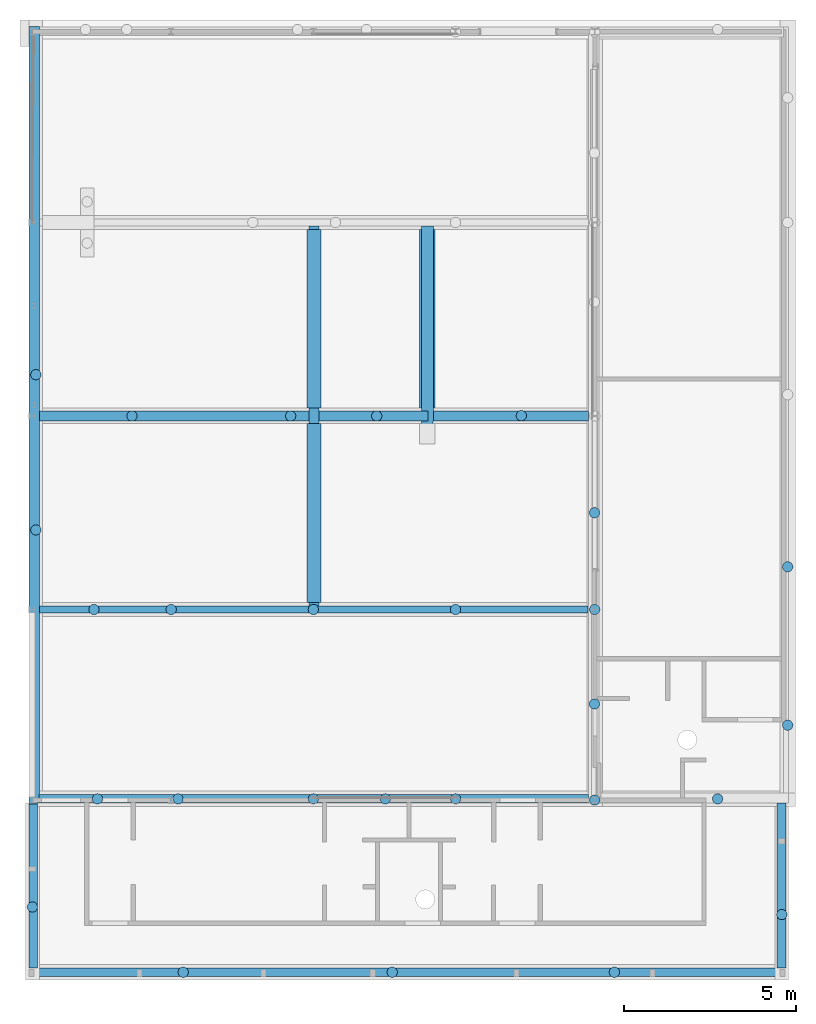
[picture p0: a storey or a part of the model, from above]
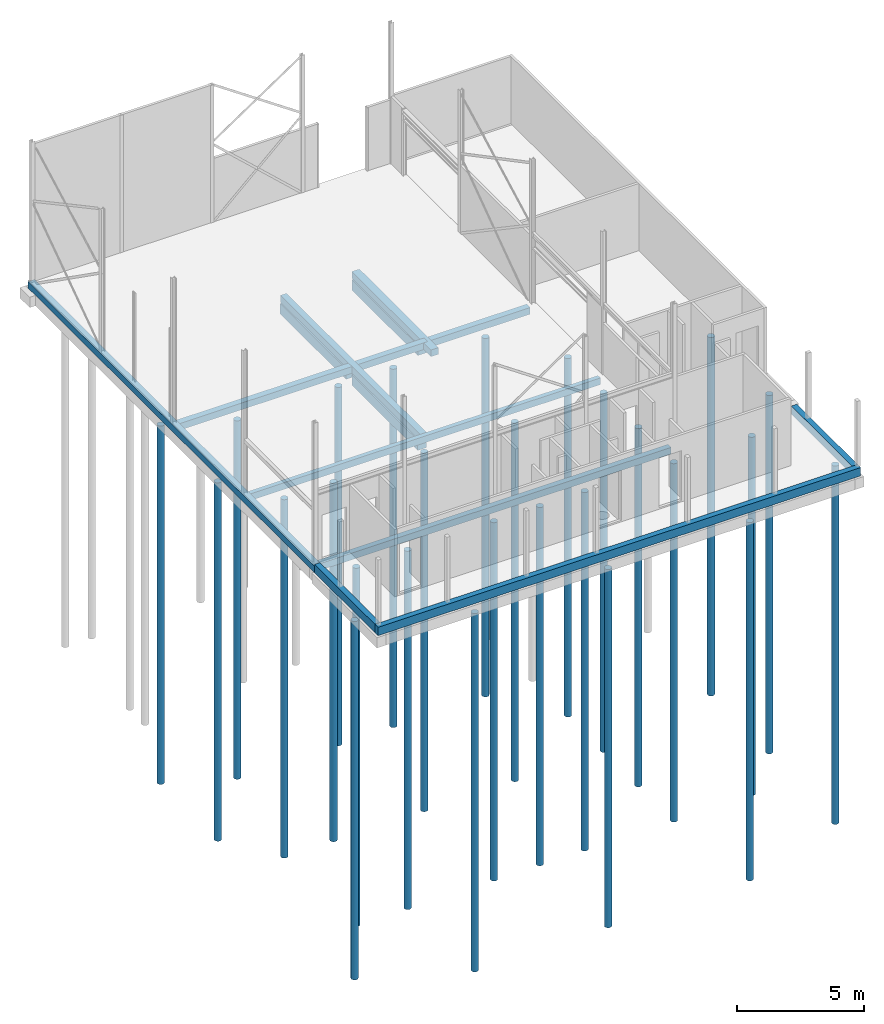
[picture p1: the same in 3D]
Properties of the parts of a building model (IFC2X3)

# File
Description: ViewDefinition [CoordinationView_V2.0], RevitIdentifiers [VersionGUID: 5828a532-ac90-4edb-b70e-f4cb268a2d0f, NumberOfSaves: 146], ExchangeRequirement [], CoordinateReference [CoordinateBase: Shared Coordinates]
File name: 24 144_Zevenbergen - Gymzaal_rvt22.ifc
Time: 2025-10-30T11:12:50
Organization: Dantuma-Wegkamp B.V.
Written by: ODA IFC SDK 22.8
Made in: 22.1.80.32 - IFC 22.7.0.0 - Default UI

# IfcProject, 24 144
LongName: Zevenbergen; Phase: Bouwaanvraag

# IfcSite, Default
RefLatitude: 52, 41, 47, 423400; RefLongitude: 6, 11, 40, 608444; RefElevation: 0 mm

# IfcBuildingStorey: Level:07_DW_Hoogte + naam (3)
Name | LongName | Elevation (mm)
00 begane grond | Peil | 0
01 eerste verdieping | 1e Verdieping | 3410
02 tweede verdieping | 2e Verdieping | 6700

# IfcBeam: 28_SF_LIB_HEA ligger_dw:HE140A (S235) (4)
Type - BIM Basis ILS - 4.3 Dragend: yes; 4.4 Uitwendig: no; 3.4 Entiteit: IfcBeam; 3.6 Codering - NL-SfB: 28.11; 3.6 NL-SfB omschrijving: hoofddraagconstructies - kolommen en liggers, kolom-/liggerconstructies; 4.7 Materiaal: constructiestaal S235
Classification: 28.11 Uniformat (Uniformat); Material: constructiestaal S235
BIM Basis ILS - 3.5 Naamgeving element: HE140A (S235); 3.5 Type: HE140A (S235)
Name (28_SF_LIB_HEA ligger_dw:HE140A (S235):...) | In
14341356 | 02 tweede verdieping
14342842 | 02 tweede verdieping | Group: Model Group:Group 1:14372738
14372881 | 02 tweede verdieping
14642640 | 01 eerste verdieping

# IfcBeam: 28_SF_LIB_HEA ligger_dw:HE160A (S235) (12)
Type - BIM Basis ILS - 4.3 Dragend: yes; 4.4 Uitwendig: no; 3.4 Entiteit: IfcBeam; 3.6 Codering - NL-SfB: 28.11; 3.6 NL-SfB omschrijving: hoofddraagconstructies - kolommen en liggers, kolom-/liggerconstructies; 4.7 Materiaal: constructiestaal S235
Classification: 28.11 Uniformat (Uniformat); Material: constructiestaal S235
BIM Basis ILS - 3.5 Naamgeving element: HE160A (S235); 3.5 Type: HE160A (S235)
Name (28_SF_LIB_HEA ligger_dw:HE160A (S235):...) | In
14295871 | 02 tweede verdieping | BIM Basis ILS - 4.5 Brandwerendheid: N.t.b.; 4.8 Brandwerendheid hoofddraagconstructie: N.t.b.
14296081 | 02 tweede verdieping
14296679 | 02 tweede verdieping
14296812 | 02 tweede verdieping
14296827 | 02 tweede verdieping
14297021 | 02 tweede verdieping
14297023 | 02 tweede verdieping
14297025 | 02 tweede verdieping
14297027 | 02 tweede verdieping
14328723 | 02 tweede verdieping
14577851 | 02 tweede verdieping | BIM Basis ILS - 4.5 Brandwerendheid: N.t.b.; 4.8 Brandwerendheid hoofddraagconstructie: N.t.b.
14590189 | 01 eerste verdieping

# IfcBeam: 28_SF_LIB_HEA ligger_dw:HE200A (S235) (5)
Type - BIM Basis ILS - 4.3 Dragend: yes; 4.4 Uitwendig: no; 3.4 Entiteit: IfcBeam; 3.6 Codering - NL-SfB: 28.11; 3.6 NL-SfB omschrijving: hoofddraagconstructies - kolommen en liggers, kolom-/liggerconstructies; 4.7 Materiaal: constructiestaal S235
Classification: 28.11 Uniformat (Uniformat); Material: constructiestaal S235
BIM Basis ILS - 3.5 Naamgeving element: HE200A (S235); 3.5 Type: HE200A (S235)
Name (28_SF_LIB_HEA ligger_dw:HE200A (S235):...) | In
14325914 | 00 begane grond
14549289 | 02 tweede verdieping
14549515 | 02 tweede verdieping
14551088 | 02 tweede verdieping
14561434 | 02 tweede verdieping

# IfcBeam: 28_SF_LIB_IPE ligger_dw:IPE200 (S235) (3)
In: 02 tweede verdieping
Type - BIM Basis ILS - 4.3 Dragend: yes; 4.4 Uitwendig: no; 3.4 Entiteit: IfcBeam; 3.6 Codering - NL-SfB: 28.11; 3.6 NL-SfB omschrijving: hoofddraagconstructies - kolommen en liggers, kolom-/liggerconstructies; 4.7 Materiaal: constructiestaal S235
Classification: 28.11 Uniformat (Uniformat); Material: constructiestaal S235
BIM Basis ILS - 3.5 Naamgeving element: IPE200 (S235); 3.5 Type: IPE200 (S235)
Name (28_SF_LIB_IPE ligger_dw:IPE200 (S235):...)
14329001
14329129
14391086

# IfcBeam: 28_SF_LIB_IPE ligger_dw:IPE240 (S235) (7)
Type - BIM Basis ILS - 4.3 Dragend: yes; 3.4 Entiteit: IfcBeam; 3.6 Codering - NL-SfB: 28.11; 3.6 NL-SfB omschrijving: hoofddraagconstructies - kolommen en liggers, kolom-/liggerconstructies; 4.7 Materiaal: constructiestaal S235; 4.4 Uitwendig: no
Classification: 28.11 Uniformat (Uniformat); Material: constructiestaal S235
BIM Basis ILS - 3.5 Naamgeving element: IPE240 (S235); 3.5 Type: IPE240 (S235)
Name (28_SF_LIB_IPE ligger_dw:IPE240 (S235):...) | In
14290186 | 01 eerste verdieping
14292657 | 00 begane grond
14512281 | 00 begane grond
14513124 | 00 begane grond
14552831 | 00 begane grond
14552852 | 00 begane grond
14552968 | 00 begane grond

# IfcBeam: 28_SF_LIB_L ligger gelijkbenig_dw:L50x50x5 (S235) (18)
In: 02 tweede verdieping
Type - BIM Basis ILS - 4.3 Dragend: yes; 4.4 Uitwendig: no; 3.4 Entiteit: IfcBeam; 3.6 Codering - NL-SfB: 28.11; 3.6 NL-SfB omschrijving: hoofddraagconstructies - kolommen en liggers, kolom-/liggerconstructies; 4.7 Materiaal: constructiestaal S235
Classification: 28.11 Uniformat (Uniformat); Material: constructiestaal S235
BIM Basis ILS - 3.5 Naamgeving element: L50x50x5 (S235); 3.5 Type: L50x50x5 (S235)
Name (28_SF_LIB_L ligger gelijkbenig_dw:L50x50x5 (S235):...)
14347161
14347278
14347650
14347838
14347931
14347933
14348421
14348501
14349087
14349460
14349540
14349542
14349848
14350011
14470697
14470783
14581076
14581078

# IfcBeam: 28_SF_LIB_L ligger gelijkbenig_dw:L80x80x6 (S235) (6)
In: 02 tweede verdieping
Type - BIM Basis ILS - 4.3 Dragend: yes; 4.4 Uitwendig: no; 3.4 Entiteit: IfcBeam; 3.6 Codering - NL-SfB: 28.11; 3.6 NL-SfB omschrijving: hoofddraagconstructies - kolommen en liggers, kolom-/liggerconstructies; 4.7 Materiaal: constructiestaal S235
Classification: 28.11 Uniformat (Uniformat); Material: constructiestaal S235
BIM Basis ILS - 3.5 Naamgeving element: L80x80x6 (S235); 3.5 Type: L80x80x6 (S235)
Name (28_SF_LIB_L ligger gelijkbenig_dw:L80x80x6 (S235):...)
14296928
14296930
14296932
14296934
14296959
14296990

# IfcBeam: 28_SF_LIB_UNP ligger_dw:UNP140 (S235) (23)
Type - BIM Basis ILS - 4.3 Dragend: yes; 4.4 Uitwendig: no; 3.4 Entiteit: IfcBeam; 3.6 Codering - NL-SfB: 28.11; 3.6 NL-SfB omschrijving: hoofddraagconstructies - kolommen en liggers, kolom-/liggerconstructies; 4.7 Materiaal: constructiestaal S235
Classification: 28.11 Uniformat (Uniformat); Material: constructiestaal S235
BIM Basis ILS - 3.5 Naamgeving element: UNP140 (S235); 3.5 Type: UNP140 (S235)
Name (28_SF_LIB_UNP ligger_dw:UNP140 (S235):...) | In
14398224 | 01 eerste verdieping
14399182 | 01 eerste verdieping
14399587 | 01 eerste verdieping
14402766 | 00 begane grond
14408845 | 02 tweede verdieping
14409364 | 02 tweede verdieping
14409934 | 01 eerste verdieping
14410029 | 01 eerste verdieping
14410105 | 01 eerste verdieping
14410157 | 01 eerste verdieping
14410337 | 01 eerste verdieping
14410354 | 01 eerste verdieping
14410582 | 01 eerste verdieping
14410927 | 01 eerste verdieping
14410929 | 01 eerste verdieping
14411169 | 01 eerste verdieping
14411171 | 01 eerste verdieping
14411344 | 01 eerste verdieping
14411425 | 01 eerste verdieping
14411487 | 01 eerste verdieping
14411551 | 01 eerste verdieping
14412489 | 01 eerste verdieping
14412908 | 01 eerste verdieping

# IfcBeam: 28_SF_LIB_UNP ligger_dw:UNP160 (S235) (4)
Type - BIM Basis ILS - 4.3 Dragend: yes; 4.4 Uitwendig: no; 3.4 Entiteit: IfcBeam; 3.6 Codering - NL-SfB: 28.11; 3.6 NL-SfB omschrijving: hoofddraagconstructies - kolommen en liggers, kolom-/liggerconstructies; 4.7 Materiaal: constructiestaal S235
Classification: 28.11 Uniformat (Uniformat); Material: constructiestaal S235
BIM Basis ILS - 3.5 Naamgeving element: UNP160 (S235); 3.5 Type: UNP160 (S235)
Name (28_SF_LIB_UNP ligger_dw:UNP160 (S235):...) | In
14339130 | 01 eerste verdieping
14387959 | 01 eerste verdieping
14400505 | 01 eerste verdieping
14402275 | 00 begane grond

# IfcBeam: 28_SF_LIB_UNP ligger_dw:UNP180 (S235), 28_SF_LIB_UNP ligger_dw:UNP180 (S235):14643737
In: 01 eerste verdieping
Type - BIM Basis ILS - 4.3 Dragend: yes; 4.4 Uitwendig: no; 3.4 Entiteit: IfcBeam; 3.6 Codering - NL-SfB: 28.11; 3.6 NL-SfB omschrijving: hoofddraagconstructies - kolommen en liggers, kolom-/liggerconstructies; 4.7 Materiaal: constructiestaal S235
Classification: 28.11 Uniformat (Uniformat); Material: constructiestaal S235
BIM Basis ILS - 3.5 Naamgeving element: UNP180 (S235); 3.5 Type: UNP180 (S235)

# IfcBeam: 28_SF_LIB_UNP ligger_dw:UNP240 (S235) (7)
Type - BIM Basis ILS - 4.3 Dragend: yes; 4.4 Uitwendig: no; 3.4 Entiteit: IfcBeam; 3.6 Codering - NL-SfB: 28.11; 3.6 NL-SfB omschrijving: hoofddraagconstructies - kolommen en liggers, kolom-/liggerconstructies; 4.7 Materiaal: constructiestaal S235
Classification: 28.11 Uniformat (Uniformat); Material: constructiestaal S235; Group: Model Group:kader:14382562
BIM Basis ILS - 3.5 Naamgeving element: UNP240 (S235); 3.5 Type: UNP240 (S235)
Name (28_SF_LIB_UNP ligger_dw:UNP240 (S235):...) | In
14382544 | 01 eerste verdieping
14382546 | 01 eerste verdieping
14382549 | 01 eerste verdieping
14382552 | 01 eerste verdieping
14382555 | 01 eerste verdieping
14382557 | 02 tweede verdieping
14382559 | 01 eerste verdieping

# IfcBeam: 28_SF_LIB_houten ligger rechthoekig_dw:200x1050 (GL28h), 28_SF_LIB_houten ligger rechthoekig_dw:200x1050 (GL28h):14293752
In: 01 eerste verdieping
Type - BIM Basis ILS - 4.3 Dragend: yes; 4.4 Uitwendig: yes; 3.4 Entiteit: IfcBeam; 3.6 Codering - NL-SfB: 28.11; 3.6 NL-SfB omschrijving: hoofddraagconstructies - kolommen en liggers, kolom-/liggerconstructies; 4.7 Materiaal: constructiehout GL28h
Classification: 28.11 Uniformat (Uniformat); Material: constructiehout GL28h
BIM Basis ILS - 3.5 Naamgeving element: 200x1050 (GL28h); 3.5 Type: 200x1050 (GL28h); 4.5 Brandwerendheid: N.t.b.; 4.8 Brandwerendheid hoofddraagconstructie: N.t.b.

# IfcBeam: 28_SF_LIB_houten ligger rechthoekig_dw:200x960 (GL28h) (2)
In: 02 tweede verdieping
Type - BIM Basis ILS - 4.3 Dragend: yes; 4.4 Uitwendig: yes; 3.4 Entiteit: IfcBeam; 3.6 Codering - NL-SfB: 28.11; 3.6 NL-SfB omschrijving: hoofddraagconstructies - kolommen en liggers, kolom-/liggerconstructies; 4.7 Materiaal: constructiehout GL28h
Classification: 28.11 Uniformat (Uniformat); Material: constructiehout GL28h
BIM Basis ILS - 3.5 Naamgeving element: 200x960 (GL28h); 3.5 Type: 200x960 (GL28h); 4.5 Brandwerendheid: N.t.b.; 4.8 Brandwerendheid hoofddraagconstructie: N.t.b.
Name (28_SF_LIB_houten ligger rechthoekig_dw:200x960 (GL28h):...) | Group
14291663 | Model Group:SPANT:14293701
14293783 | Model Group:SPANT:14293785

# IfcBeam: 28_SF_LIB_houten ligger rechthoekig_dw:70x245 (C24) (87)
In: 01 eerste verdieping
Type - BIM Basis ILS - 4.3 Dragend: yes; 4.4 Uitwendig: yes; 3.4 Entiteit: IfcBeam; 3.6 Codering - NL-SfB: 28.11; 3.6 NL-SfB omschrijving: hoofddraagconstructies - kolommen en liggers, kolom-/liggerconstructies; 4.7 Materiaal: constructiehout C24
Classification: 28.11 Uniformat (Uniformat); Material: constructiehout C24
BIM Basis ILS - 3.5 Naamgeving element: 70x245 (C24); 3.5 Type: 70x245 (C24)
Name (28_SF_LIB_houten ligger rechthoekig_dw:70x245 (C24):...)
14288473
14288544
14288929
14289023
14300772
14313485
14313488
14313491
14313494
14313497
14313500
14313503
14313506
14313509
14313512
14313515
14313518
14313521
14313524
14313527
14313530
14313533
14313536
14313539
14313542
14313545
14313548
14313551
14313554
14313557
14313560
14313563
14313566
14313569
14313572
14313575
14313578
14313581
14313584
14313587
14313590
14313593
14313596
14313599
14313602
14313605
14313608
14313611
14313614
14313617
14313620
14313623
14313626
14313629
14313632
14313635
14313638
14313641
14314583
14314586
14314589
14314592
14314595
14314598
14314601
14314604
14314607
14314610
14314613
14314616
14314619
14314622
14314625
14314784
14314787
14314790
14314793
14314796
14314799
14314802
14314805
14314808
14314811
14314814
14314817
14382725
14382727

# IfcBeam: 28_SF_LIB_koker ligger_dw:K60x60x6 (S275) (6)
In: 02 tweede verdieping
Type - BIM Basis ILS - 4.3 Dragend: yes; 4.4 Uitwendig: no; 3.4 Entiteit: IfcBeam; 3.6 Codering - NL-SfB: 28.11; 3.6 NL-SfB omschrijving: hoofddraagconstructies - kolommen en liggers, kolom-/liggerconstructies; 4.7 Materiaal: constructiestaal S275
Classification: 28.11 Uniformat (Uniformat); Material: constructiestaal S275
BIM Basis ILS - 3.5 Naamgeving element: K60x60x6 (S275); 3.5 Type: K60x60x6 (S275)
Name (28_SF_LIB_koker ligger_dw:K60x60x6 (S275):...)
14296961
14296963
14296965
14296992
14296994
14296996

# IfcBeam: 28_SF_LIB_strip ligger_dw:strip 100x8 (S235) (16)
In: 00 begane grond
Type - BIM Basis ILS - 4.3 Dragend: yes; 4.4 Uitwendig: no; 3.4 Entiteit: IfcBeam; 3.6 Codering - NL-SfB: 28.11; 3.6 NL-SfB omschrijving: hoofddraagconstructies - kolommen en liggers, kolom-/liggerconstructies; 4.7 Materiaal: constructiestaal S235
Classification: 28.11 Uniformat (Uniformat); Material: constructiestaal S235
BIM Basis ILS - 3.5 Naamgeving element: strip 100x8 (S235); 3.5 Type: strip 100x8 (S235)
Name (28_SF_LIB_strip ligger_dw:strip 100x8 (S235):...)
14340948
14341179
14341295
14341358
14341360
14341362
14341364
14343473 | Group: Model Group:Group 1:14372738
14343555 | Group: Model Group:Group 1:14372738
14343773 | Group: Model Group:Group 1:14372738
14344218 | Group: Model Group:Group 1:14372738
14372883
14372885
14372889
14459453
14463984

# IfcBeam: 28_SF_UN_koker ligger_dw:K180x180x10 (S355) (5)
Type - BIM Basis ILS - 4.3 Dragend: yes; 4.4 Uitwendig: no; 3.4 Entiteit: IfcBeam; 3.6 Codering - NL-SfB: 28.11; 3.6 NL-SfB omschrijving: hoofddraagconstructies - kolommen en liggers, kolom-/liggerconstructies; 4.7 Materiaal: constructiestaal S355
Classification: 28.11 Uniformat (Uniformat); Material: constructiestaal S355
BIM Basis ILS - 3.5 Naamgeving element: K180x180x10 (S355); 3.5 Type: K180x180x10 (S355)
Name (28_SF_UN_koker ligger_dw:K180x180x10 (S355):...) | In
14571354 | 00 begane grond
14571927 | 01 eerste verdieping
14572121 | 01 eerste verdieping
14572268 | 01 eerste verdieping
14572367 | 01 eerste verdieping

# IfcBeam: 28_SF_UN_raveelijzer_dw:raveelijzer - vloer 200 (2)
In: 01 eerste verdieping
Type - PredefinedType: BEAM; Classification: 28.11 Uniformat (Uniformat); Material: constructiestaal
Type - BIM Basis ILS - 4.3 Dragend: yes; 4.4 Uitwendig: no; 3.4 Entiteit: IfcBeam; 3.6 Codering - NL-SfB: 28.11; 3.6 NL-SfB omschrijving: hoofddraagconstructies - kolommen en liggers, kolom-/liggerconstructies; 4.7 Materiaal: constructiestaal
BIM Basis ILS - 3.5 Naamgeving element: raveelijzer - vloer 200; 3.5 Type: raveelijzer - vloer 200
Name (28_SF_UN_raveelijzer_dw:raveelijzer - vloer 200:...)
14405406
14405581

# IfcBuildingElementProxy: 00_GM_UN_referentiekubus_dw:referentiekubus l-v-o, 00_GM_UN_referentiekubus_dw:referentiekubus l-v-o:8439740
In: 00 begane grond
Type - Classification: 0-.00 Uniformat (Uniformat); Material: DW groen - 176-172-60, DW bruin - 64-48-0
Type - BIM Basis ILS - 3.4 Entiteit: IfcObject; 3.6 Codering - NL-SfB: 0-.00; 3.6 NL-SfB omschrijving: indirecte projectvoorzieningen
BIM Basis ILS - 3.5 Naamgeving element: referentiekubus l-v-o; 3.5 Type: referentiekubus l-v-o

# IfcColumn: 28_SCO_TLB_HEA kolom_dw:HE160A (S235) (7)
In: 00 begane grond
Type - PredefinedType: COLUMN; Classification: 28.11 Uniformat (Uniformat); Material: constructiestaal S235
Type - BIM Basis ILS - 4.3 Dragend: yes; 4.4 Uitwendig: yes; 3.4 Entiteit: IfcColumn; 3.6 Codering - NL-SfB: 28.11; 3.6 NL-SfB omschrijving: hoofddraagconstructies - kolommen en liggers, kolom-/liggerconstructies; 4.7 Materiaal: constructiestaal S235
BIM Basis ILS - 3.5 Naamgeving element: HE160A (S235); 3.5 Type: HE160A (S235)
Name (28_SCO_TLB_HEA kolom_dw:HE160A (S235):...)
14284300 | Group: Model Group:SK2:14284304
14284488 | Group: Model Group:SK2:14284492
14284511 | Group: Model Group:SK2:14284515
14284992
14285208
14285229
14353443

# IfcColumn: 28_SCO_TLB_HEA kolom_dw:HE180A (S235) (10)
In: 00 begane grond
Type - PredefinedType: COLUMN; Classification: 28.11 Uniformat (Uniformat); Material: constructiestaal S235
Type - BIM Basis ILS - 4.3 Dragend: yes; 4.4 Uitwendig: yes; 3.4 Entiteit: IfcColumn; 3.6 Codering - NL-SfB: 28.11; 3.6 NL-SfB omschrijving: hoofddraagconstructies - kolommen en liggers, kolom-/liggerconstructies; 4.7 Materiaal: constructiestaal S235
BIM Basis ILS - 3.5 Naamgeving element: HE180A (S235); 3.5 Type: HE180A (S235)
Name (28_SCO_TLB_HEA kolom_dw:HE180A (S235):...)
14284682 | Group: Model Group:SPANT:14293701
14285795 | Group: Model Group:SPANT:14293701
14293748
14293750
14293779 | Group: Model Group:SPANT:14293785
14293781 | Group: Model Group:SPANT:14293785
14295869
14295873
14578198
14578254

# IfcColumn: 28_SCO_TLB_IPE kolom_dw:IPE160 (S235) (8)
In: 01 eerste verdieping
Type - PredefinedType: COLUMN; Classification: 28.11 Uniformat (Uniformat); Material: constructiestaal S235
Type - BIM Basis ILS - 4.3 Dragend: yes; 4.4 Uitwendig: yes; 3.4 Entiteit: IfcColumn; 3.6 Codering - NL-SfB: 28.11; 3.6 NL-SfB omschrijving: hoofddraagconstructies - kolommen en liggers, kolom-/liggerconstructies; 4.7 Materiaal: constructiestaal S235
BIM Basis ILS - 3.5 Naamgeving element: IPE160 (S235); 3.5 Type: IPE160 (S235)
Name (28_SCO_TLB_IPE kolom_dw:IPE160 (S235):...)
14328455
14328642
14328661
14329676
14381776
14392654
14409115
14409175

# IfcColumn: 28_SCO_TLB_UNP kolom_dw:UNP140 (S235) (4)
In: 01 eerste verdieping
Type - PredefinedType: COLUMN; Classification: 28.11 Uniformat (Uniformat); Material: constructiestaal S235
Type - BIM Basis ILS - 4.3 Dragend: yes; 4.4 Uitwendig: yes; 3.4 Entiteit: IfcColumn; 3.6 Codering - NL-SfB: 28.11; 3.6 NL-SfB omschrijving: hoofddraagconstructies - kolommen en liggers, kolom-/liggerconstructies; 4.7 Materiaal: constructiestaal S235
BIM Basis ILS - 3.5 Naamgeving element: UNP140 (S235); 3.5 Type: UNP140 (S235)
Name (28_SCO_TLB_UNP kolom_dw:UNP140 (S235):...)
14398592
14398738
14410425
14410427

# IfcColumn: 28_SCO_TLB_UNP kolom_dw:UNP160 (S235) (5)
In: 00 begane grond
Type - PredefinedType: COLUMN; Classification: 28.11 Uniformat (Uniformat); Material: constructiestaal S235
Type - BIM Basis ILS - 4.3 Dragend: yes; 4.4 Uitwendig: yes; 3.4 Entiteit: IfcColumn; 3.6 Codering - NL-SfB: 28.11; 3.6 NL-SfB omschrijving: hoofddraagconstructies - kolommen en liggers, kolom-/liggerconstructies; 4.7 Materiaal: constructiestaal S235
BIM Basis ILS - 3.5 Naamgeving element: UNP160 (S235); 3.5 Type: UNP160 (S235)
Name (28_SCO_TLB_UNP kolom_dw:UNP160 (S235):...)
14387786
14388673
14402511
14555188
14555243

# IfcColumn: 28_SCO_TLB_houten kolom rechthoekig_dw:150x200 (C24) (9)
In: 00 begane grond
Type - PredefinedType: COLUMN; Classification: 28.11 Uniformat (Uniformat); Material: constructiehout C24
Type - BIM Basis ILS - 4.3 Dragend: yes; 4.4 Uitwendig: yes; 3.4 Entiteit: IfcColumn; 3.6 Codering - NL-SfB: 28.11; 3.6 NL-SfB omschrijving: hoofddraagconstructies - kolommen en liggers, kolom-/liggerconstructies; 4.7 Materiaal: constructiehout C24
BIM Basis ILS - 3.5 Naamgeving element: 150x200 (C24); 3.5 Type: 150x200 (C24)
Name (28_SCO_TLB_houten kolom rechthoekig_dw:150x200 (C24):...) | Group
14282308
14283523
14283591 | Model Group:HK1:14283595
14283735 | Model Group:HK1:14283739
14283756 | Model Group:HK1:14283760
14283779 | Model Group:HK1:14283783
14283800 | Model Group:HK1:14283804
14283819
14366132

# IfcFooting: 16_SF_LIB_funderingsbalk_dw:150x400 (ihwg), 16_SF_LIB_funderingsbalk_dw:150x400 (ihwg):14532306
In: 00 begane grond
Type - Classification: 16.11 Uniformat (Uniformat); Material: ihwg beton
BIM Basis ILS - 4.3 Dragend: yes; 3.4 Entiteit: IfcFooting; 3.5 Naamgeving element: 150x400 (ihwg); 3.5 Type: 150x400 (ihwg); 3.6 Codering - NL-SfB: 16.11; 3.6 NL-SfB omschrijving: funderingsconstructies - voeten en balken, fundatie voeten; 4.7 Materiaal: ihwg beton; 4.8 Brandwerendheid hoofddraagconstructie: N.t.b.

# IfcFooting: 16_SF_LIB_funderingsbalk_dw:200x350 (ihwg) (2)
In: 00 begane grond
Type - Classification: 16.11 Uniformat (Uniformat); Material: ihwg beton
BIM Basis ILS - 4.3 Dragend: yes; 3.4 Entiteit: IfcFooting; 3.5 Naamgeving element: 200x350 (ihwg); 3.5 Type: 200x350 (ihwg); 3.6 Codering - NL-SfB: 16.11; 3.6 NL-SfB omschrijving: funderingsconstructies - voeten en balken, fundatie voeten; 4.7 Materiaal: ihwg beton; 4.8 Brandwerendheid hoofddraagconstructie: N.t.b.
Name (16_SF_LIB_funderingsbalk_dw:200x350 (ihwg):...)
14528531
14528994

# IfcFooting: 16_SF_LIB_funderingsbalk_dw:250x320 (ihwg) (2)
In: 00 begane grond
Type - Classification: 16.11 Uniformat (Uniformat); Material: ihwg beton
BIM Basis ILS - 4.3 Dragend: yes; 3.4 Entiteit: IfcFooting; 3.5 Naamgeving element: 250x320 (ihwg); 3.5 Type: 250x320 (ihwg); 3.6 Codering - NL-SfB: 16.11; 3.6 NL-SfB omschrijving: funderingsconstructies - voeten en balken, fundatie voeten; 4.7 Materiaal: ihwg beton; 4.8 Brandwerendheid hoofddraagconstructie: N.t.b.
Name (16_SF_LIB_funderingsbalk_dw:250x320 (ihwg):...)
14445392
14450429

# IfcFooting: 16_SF_LIB_funderingsbalk_dw:250x400 (ihwg) (3)
In: 00 begane grond
Type - Classification: 16.11 Uniformat (Uniformat); Material: ihwg beton
BIM Basis ILS - 4.3 Dragend: yes; 3.4 Entiteit: IfcFooting; 3.5 Naamgeving element: 250x400 (ihwg); 3.5 Type: 250x400 (ihwg); 3.6 Codering - NL-SfB: 16.11; 3.6 NL-SfB omschrijving: funderingsconstructies - voeten en balken, fundatie voeten; 4.7 Materiaal: ihwg beton; 4.8 Brandwerendheid hoofddraagconstructie: N.t.b.
Name (16_SF_LIB_funderingsbalk_dw:250x400 (ihwg):...)
14439468
14443439
14443543

# IfcFooting: 16_SF_LIB_funderingsbalk_dw:260x500 (ihwg), 16_SF_LIB_funderingsbalk_dw:260x500 (ihwg):14303276
In: 00 begane grond
Type - Classification: 16.12 Uniformat (Uniformat); Material: ihwg beton
BIM Basis ILS - 4.3 Dragend: yes; 3.4 Entiteit: IfcFooting; 3.5 Naamgeving element: 260x500 (ihwg); 3.5 Type: 260x500 (ihwg); 3.6 Codering - NL-SfB: 16.12; 3.6 NL-SfB omschrijving: funderingsconstructies - voeten en balken, fundatie balken; 4.7 Materiaal: ihwg beton; 4.8 Brandwerendheid hoofddraagconstructie: N.t.b.

# IfcFooting: 16_SF_LIB_funderingsbalk_dw:280x350 (ihwg) (4)
In: 00 begane grond
Type - Classification: 16.11 Uniformat (Uniformat); Material: ihwg beton
BIM Basis ILS - 4.3 Dragend: yes; 3.4 Entiteit: IfcFooting; 3.5 Naamgeving element: 280x350 (ihwg); 3.5 Type: 280x350 (ihwg); 3.6 Codering - NL-SfB: 16.11; 3.6 NL-SfB omschrijving: funderingsconstructies - voeten en balken, fundatie voeten; 4.7 Materiaal: ihwg beton; 4.8 Brandwerendheid hoofddraagconstructie: N.t.b.
Name (16_SF_LIB_funderingsbalk_dw:280x350 (ihwg):...)
14491663
14493827
14494834
14495136

# IfcFooting: 16_SF_LIB_funderingsbalk_dw:300x320 (ihwg) (2)
In: 00 begane grond
Type - Classification: 16.11 Uniformat (Uniformat); Material: ihwg beton
BIM Basis ILS - 4.3 Dragend: yes; 3.4 Entiteit: IfcFooting; 3.5 Naamgeving element: 300x320 (ihwg); 3.5 Type: 300x320 (ihwg); 3.6 Codering - NL-SfB: 16.11; 3.6 NL-SfB omschrijving: funderingsconstructies - voeten en balken, fundatie voeten; 4.7 Materiaal: ihwg beton; 4.8 Brandwerendheid hoofddraagconstructie: N.t.b.
Name (16_SF_LIB_funderingsbalk_dw:300x320 (ihwg):...)
14448791
14449513

# IfcFooting: 16_SF_LIB_funderingsbalk_dw:300x400 (ihwg) (2)
In: 00 begane grond
Type - Classification: 16.11 Uniformat (Uniformat); Material: ihwg beton
BIM Basis ILS - 4.3 Dragend: yes; 3.4 Entiteit: IfcFooting; 3.5 Naamgeving element: 300x400 (ihwg); 3.5 Type: 300x400 (ihwg); 3.6 Codering - NL-SfB: 16.11; 3.6 NL-SfB omschrijving: funderingsconstructies - voeten en balken, fundatie voeten; 4.7 Materiaal: ihwg beton; 4.8 Brandwerendheid hoofddraagconstructie: N.t.b.
Name (16_SF_LIB_funderingsbalk_dw:300x400 (ihwg):...)
14531801
14533458

# IfcFooting: 16_SF_LIB_funderingsbalk_dw:350x450 (ihwg), 16_SF_LIB_funderingsbalk_dw:350x450 (ihwg):14495497
In: 00 begane grond
Type - Classification: 16.11 Uniformat (Uniformat); Material: ihwg beton
BIM Basis ILS - 4.3 Dragend: yes; 3.4 Entiteit: IfcFooting; 3.5 Naamgeving element: 350x450 (ihwg); 3.5 Type: 350x450 (ihwg); 3.6 Codering - NL-SfB: 16.11; 3.6 NL-SfB omschrijving: funderingsconstructies - voeten en balken, fundatie voeten; 4.7 Materiaal: ihwg beton; 4.8 Brandwerendheid hoofddraagconstructie: N.t.b.

# IfcFooting: 16_SF_LIB_funderingsbalk_dw:400x500 (ihwg) (8)
In: 00 begane grond
Type - Classification: 16.12 Uniformat (Uniformat); Material: ihwg beton
BIM Basis ILS - 4.3 Dragend: yes; 3.4 Entiteit: IfcFooting; 3.5 Naamgeving element: 400x500 (ihwg); 3.5 Type: 400x500 (ihwg); 3.6 Codering - NL-SfB: 16.12; 3.6 NL-SfB omschrijving: funderingsconstructies - voeten en balken, fundatie balken; 4.7 Materiaal: ihwg beton; 4.8 Brandwerendheid hoofddraagconstructie: N.t.b.
Name (16_SF_LIB_funderingsbalk_dw:400x500 (ihwg):...)
14302218
14302364
14302961
14305030
14311621
14489020
14489022
14615878

# IfcFooting: 16_SF_LIB_funderingsbalk_dw:450x500 (ihwg) (8)
In: 00 begane grond
Type - Classification: 16.12 Uniformat (Uniformat); Material: ihwg beton
BIM Basis ILS - 4.3 Dragend: yes; 3.4 Entiteit: IfcFooting; 3.5 Naamgeving element: 450x500 (ihwg); 3.5 Type: 450x500 (ihwg); 3.6 Codering - NL-SfB: 16.12; 3.6 NL-SfB omschrijving: funderingsconstructies - voeten en balken, fundatie balken; 4.7 Materiaal: ihwg beton
Name (16_SF_LIB_funderingsbalk_dw:450x500 (ihwg):...) | 4.8 Brandwerendheid hoofddraagconstructie
14303714 | N.t.b.
14303831 | N.t.b.
14305015 | N.t.b.
14305122 | N.t.b.
14365426
14488232 | N.t.b.
14488643 | N.t.b.
14499392 | N.t.b.

# IfcFooting: 16_SF_LIB_funderingsbalk_dw:550x500 (ihwg), 16_SF_LIB_funderingsbalk_dw:550x500 (ihwg):14302722
In: 00 begane grond
Type - Classification: 16.12 Uniformat (Uniformat); Material: ihwg beton
BIM Basis ILS - 4.3 Dragend: yes; 3.4 Entiteit: IfcFooting; 3.5 Naamgeving element: 550x500 (ihwg); 3.5 Type: 550x500 (ihwg); 3.6 Codering - NL-SfB: 16.12; 3.6 NL-SfB omschrijving: funderingsconstructies - voeten en balken, fundatie balken; 4.7 Materiaal: ihwg beton; 4.8 Brandwerendheid hoofddraagconstructie: N.t.b.

# IfcFooting: 16_SF_LIB_funderingsbalk_dw:poer 400x600, 16_SF_LIB_funderingsbalk_dw:poer 400x600:14610776
In: 00 begane grond
Type - Classification: 16.12 Uniformat (Uniformat); Material: ihwg beton
BIM Basis ILS - 4.3 Dragend: yes; 3.4 Entiteit: IfcFooting; 3.5 Naamgeving element: poer 400x600; 3.5 Type: poer 400x600; 3.6 Codering - NL-SfB: 16.12; 3.6 NL-SfB omschrijving: funderingsconstructies - voeten en balken, fundatie balken; 4.7 Materiaal: ihwg beton; 4.8 Brandwerendheid hoofddraagconstructie: N.t.b.

# IfcOpeningElement: Opening (12)
Name | In | Classification
8 x Basic Wall:21.22_WA_TLB_kalkzandsteen 120-CS12_dw:14271793 | 00 begane grond | 21.22 Uniformat (Uniformat)
Floor:23.21_FL_LB_geïsoleerde kanaalplaatvloer 200-Rc=6,5_dw:14281954 | 00 begane grond | 23.21 Uniformat (Uniformat) | BIM Basis ILS - 3.5 Naamgeving element: Ø540 (kl); 3.5 Type: Ø540 (kl)
Floor:23.21_FL_LB_geïsoleerde kanaalplaatvloer 200-Rc=6,5_dw:14282030 | 00 begane grond | 23.21 Uniformat (Uniformat) | BIM Basis ILS - 3.5 Naamgeving element: Ø540 (kl); 3.5 Type: Ø540 (kl)
2 x Floor:23.21_FL_LB_kanaalplaatvloer 200_dw:14271668 | 01 eerste verdieping | 23.21 Uniformat (Uniformat)

# IfcPile: 17_SFO_TLB_mortelschroefpaal_dw:Ø300_ihwg fund_type 01 (46)
In: 00 begane grond
Classification: 17.12 Uniformat (Uniformat); Material: ihwg beton
BIM Basis ILS - 4.3 Dragend: yes; 3.4 Entiteit: IfcPile; 3.5 Naamgeving element: Ø300_ihwg fund_type 01; 3.5 Type: Ø300_ihwg fund_type 01; 3.6 Codering - NL-SfB: 17.12; 3.6 NL-SfB omschrijving: paalfunderingen - niet geheid, dragende palen - geschroefd; 4.7 Materiaal: ihwg beton
Name (17_SFO_TLB_mortelschroefpaal_dw:Ø300_ihwg fund_type 01:...) | 4.8 Paalnummer
14378213 | 20
14378246 | 16
14378260 | 1
14378296 | 5
14378509 | 12
14378521 | 13
14378535 | 14
14378647 | 21
14378659 | 23
14378679 | 24
14378726 | 29
14378729 | 30
14378732 | 31
14378735 | 25
14378764 | 28
14378807 | 32
14378875 | 35
14378899 | 36
14378911 | 37
14378925 | 39
14378951 | 41
14378963 | 34
14379524 | 27
14379551 | 8
14379637 | 19
14379766 | 44
14379809 | 45
14379823 | 46
14379835 | 43
14412164 | 15
14593934 | 3
14593946 | 4
14594007 | 6
14594023 | 7
14594874 | 2
14594898 | 9
14594959 | 17
14595027 | 33
14595039 | 40
14595088 | 11
14595256 | 18
14595272 | 26
14595284 | 42
14595373 | 38
14595656 | 22
14611114 | 10

# IfcSlab: Floor:23.20_FL_LB_druklaag 80_dw, Floor:23.20_FL_LB_druklaag 80_dw:14307007
In: 00 begane grond
Type - PredefinedType: FLOOR; Material: ihwg beton 80 mm
Type - BIM Basis ILS - 4.4 Uitwendig: no; 3.4 Entiteit: IfcSlab; 3.6 Codering - NL-SfB: 23.20; 3.6 NL-SfB omschrijving: vloeren - constructief, algemeen (verzamelniveau); 4.7 Materiaal: ihwg beton
Classification: 23.20 Uniformat (Uniformat)
BIM Basis ILS - 4.3 Dragend: yes; 3.5 Naamgeving element: 23.20_FL_LB_druklaag 80_dw; 3.5 Type: 23.20_FL_LB_druklaag 80_dw

# IfcSlab: Floor:23.20_FL_LB_underlayment 18_dw, Floor:23.20_FL_LB_underlayment 18_dw:14300275
In: 01 eerste verdieping
Type - PredefinedType: FLOOR; Material: underlayment 18 mm
Type - BIM Basis ILS - 4.4 Uitwendig: no; 3.4 Entiteit: IfcSlab; 3.6 Codering - NL-SfB: 23.20; 3.6 NL-SfB omschrijving: vloeren - constructief, algemeen (verzamelniveau); 4.7 Materiaal: underlayment
Classification: 23.20 Uniformat (Uniformat)
BIM Basis ILS - 4.3 Dragend: yes; 3.5 Naamgeving element: 23.20_FL_LB_underlayment 18_dw; 3.5 Type: 23.20_FL_LB_underlayment 18_dw

# IfcSlab: Floor:23.21.41_staalplaat 137 (2)
In: 02 tweede verdieping
Type - PredefinedType: FLOOR; Material: Metal Deck 137 mm
Type - BIM Basis ILS - 4.4 Uitwendig: no; 3.6 Codering - NL-SfB: 27.21; 3.6 NL-SfB omschrijving: daken - constructief, vlakke daken; 4.7 Materiaal: Metal Deck; 4.6 Warmtedoorgangscoefficient: 328,4672 W/(m²·K)
Classification: 27.21 Uniformat (Uniformat)
BIM Basis ILS - 4.3 Dragend: yes; 3.5 Naamgeving element: 23.21.41_staalplaat 137; 3.5 Type: 23.21.41_staalplaat 137
Name (Floor:23.21.41_staalplaat 137:...)
14300850
14301639

# IfcSlab: Floor:23.21_FL_LB_geïsoleerde kanaalplaatvloer 200-Rc=3,7_dw (7)
In: 00 begane grond
Type - PredefinedType: FLOOR; Material: prefab beton 200 mm, EPS vloerisolatie 120 mm
Type - BIM Basis ILS - 4.4 Uitwendig: yes; 3.4 Entiteit: IfcSlab; 3.6 Codering - NL-SfB: 23.21; 3.6 NL-SfB omschrijving: vloeren - constructief, vrijdragende vloeren; 4.7 Materiaal: prefab beton; 4.6 Isolatiewaarde: 3,7
Classification: 23.21 Uniformat (Uniformat)
BIM Basis ILS - 4.3 Dragend: yes; 3.5 Naamgeving element: 23.21_FL_LB_geïsoleerde kanaalplaatvloer 200-Rc=3,7_dw; 3.5 Type: 23.21_FL_LB_geïsoleerde kanaalplaatvloer 200-Rc=3,7_dw
Name (Floor:23.21_FL_LB_geïsoleerde kanaalplaatvloer 200-Rc=3,7_dw:...)
14281693
14281693:2
14281693:3
14281693:4
14281693:5
14281693:6
14281693:7

# IfcSlab: Floor:23.21_FL_LB_geïsoleerde kanaalplaatvloer 200-Rc=6,5_dw (2)
In: 00 begane grond
Type - PredefinedType: FLOOR; Material: prefab beton 200 mm, EPS vloerisolatie 200 mm
Type - BIM Basis ILS - 4.4 Uitwendig: yes; 3.4 Entiteit: IfcSlab; 3.6 Codering - NL-SfB: 23.21; 3.6 NL-SfB omschrijving: vloeren - constructief, vrijdragende vloeren; 4.7 Materiaal: prefab beton; 4.6 Isolatiewaarde: 6,5
Classification: 23.21 Uniformat (Uniformat)
BIM Basis ILS - 4.3 Dragend: yes; 3.5 Naamgeving element: 23.21_FL_LB_geïsoleerde kanaalplaatvloer 200-Rc=6,5_dw; 3.5 Type: 23.21_FL_LB_geïsoleerde kanaalplaatvloer 200-Rc=6,5_dw
Name (Floor:23.21_FL_LB_geïsoleerde kanaalplaatvloer 200-Rc=6,5_dw:...)
14281954
14282030

# IfcSlab: Floor:23.21_FL_LB_kanaalplaatvloer 200_dw, Floor:23.21_FL_LB_kanaalplaatvloer 200_dw:14290286
In: 01 eerste verdieping
Type - PredefinedType: FLOOR
Type - BIM Basis ILS - 4.4 Uitwendig: no; 3.4 Entiteit: IfcSlab; 3.6 Codering - NL-SfB: 23.21; 3.6 NL-SfB omschrijving: vloeren - constructief, vrijdragende vloeren; 4.7 Materiaal: prefab beton
Classification: 23.21 Uniformat (Uniformat); Material: prefab beton
BIM Basis ILS - 4.3 Dragend: yes; 3.5 Naamgeving element: 23.21_FL_LB_kanaalplaatvloer 200_dw; 3.5 Type: 23.21_FL_LB_kanaalplaatvloer 200_dw

# IfcWallStandardCase: Basic Wall:21.22_WA_TLB_kalkzandsteen 120-CS12_dw (42)
In: 00 begane grond
Type - PredefinedType: STANDARD; Material: kalkzandsteen lijmelementen CS12 120 mm
Type - BIM Basis ILS - 3.4 Entiteit: IfcWall; 3.6 Codering - NL-SfB: 21.22; 3.6 NL-SfB omschrijving: buitenwanden - constructief, spouwwanden; 4.7 Materiaal: kalkzandsteen lijmelementen CS12; 4.4 Uitwendig: yes
Classification: 21.22 Uniformat (Uniformat)
BIM Basis ILS - 3.5 Naamgeving element: 21.22_WA_TLB_kalkzandsteen 120-CS12_dw; 3.5 Type: 21.22_WA_TLB_kalkzandsteen 120-CS12_dw
Name (Basic Wall:21.22_WA_TLB_kalkzandsteen 120-CS12_dw:...) | 4.3 Dragend
14276847 | yes
14277201 | no
14277355 | no
14277423 | no
14277537 | no
14278177 | yes
14278416 | yes
14278576 | yes
14278862 | yes
14278990 | yes
14279425 | yes
14279518 | no
14279628 | yes
14279719 | yes
14279865 | yes
14279950 | yes
14280026 | yes
14280126 | yes
14280144 | yes
14280343 | no
14280706 | no
14280844 | no
14280939 | no
14281013 | no
14281081 | no
14281156 | no
14281158 | no
14281237 | no
14281239 | no
14281294 | no
14281367 | no
14281533 | no
14281639 | no
14300116 | yes
14300118 | yes
14300120 | yes
14300122 | yes
14311489 | no
14311491 | no
14315741 | no
14337542 | yes
14401574 | yes
